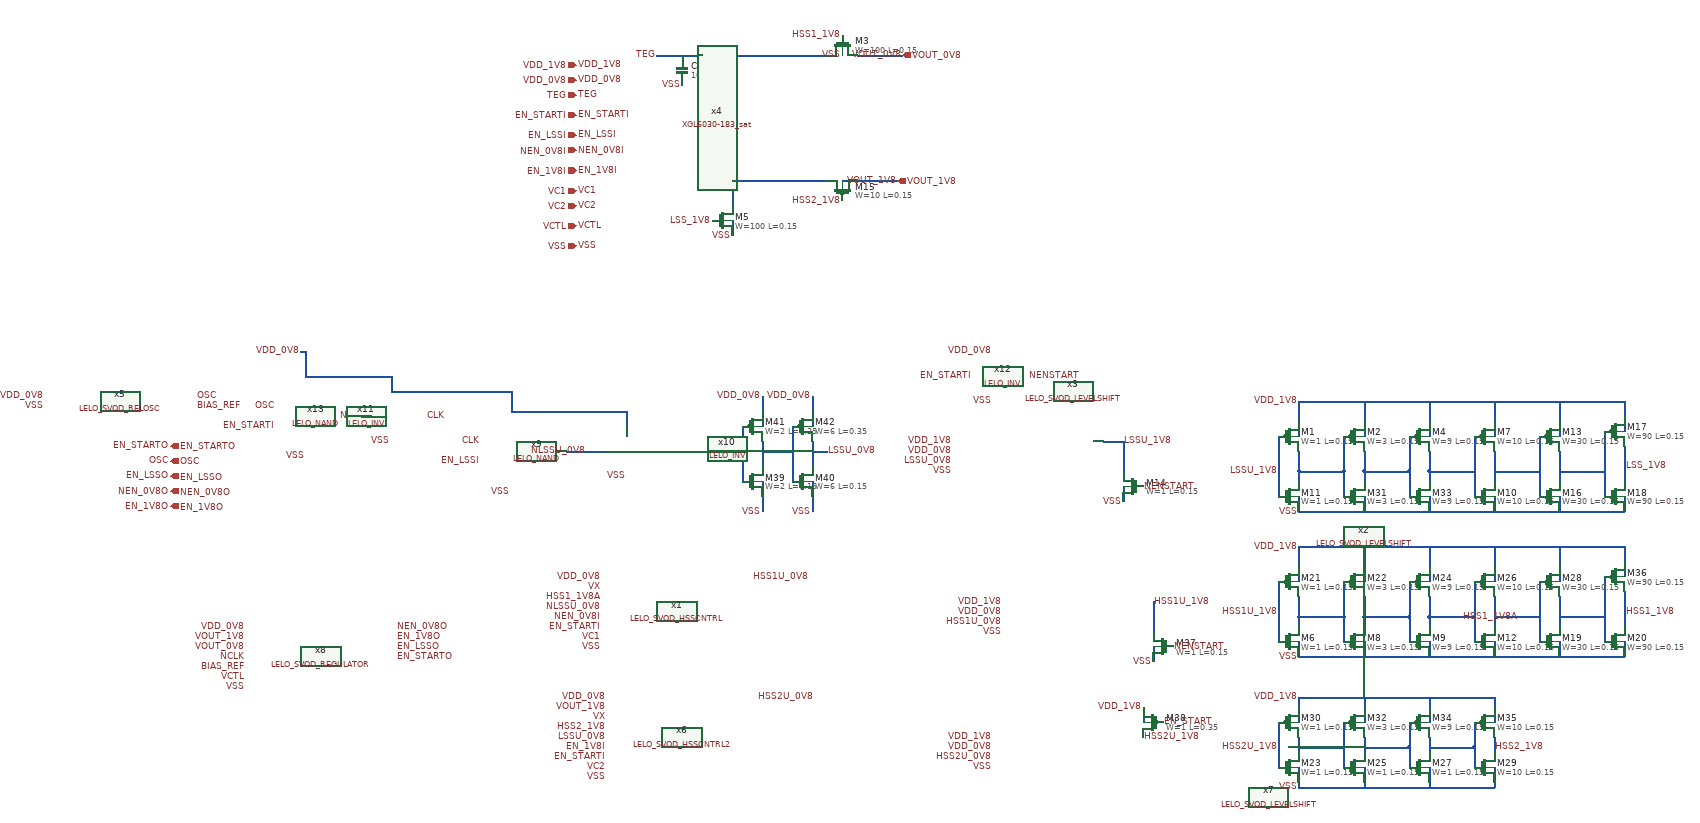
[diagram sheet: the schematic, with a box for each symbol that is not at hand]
v {xschem version=3.4.6 file_version=1.2}
G {}
K {}
V {}
S {}
E {}
N -350 -940 -290 -940 {lab=VX}
N -480 -940 -350 -940 {lab=VX}
N -480 -940 -480 -780 {lab=VX}
N -560 -940 -540 -940 {lab=TEG}
N 650 -60 650 -30 {lab=VSS}
N 1040 -150 1040 -90 {lab=#net1}
N 1040 -60 1040 -30 {lab=VSS}
N 1000 -180 1000 -60 {lab=#net2}
N 650 -110 740 -110 {lab=#net3}
N -580 -940 -560 -940 {lab=TEG}
N 1170 -150 1170 -90 {lab=#net4}
N 1170 -60 1170 -30 {lab=VSS}
N 1130 -180 1130 -60 {lab=#net1}
N 1040 -110 1130 -110 {lab=#net1}
N 1300 -160 1300 -90 {lab=LSS_1V8}
N 1300 -60 1300 -30 {lab=VSS}
N 1260 -190 1260 -60 {lab=#net4}
N 1170 -110 1260 -110 {lab=#net4}
N -230 -940 -140 -940 {lab=VOUT_0V8}
N 650 -250 1230 -250 {lab=VDD_1V8}
N 1040 -250 1040 -210 {lab=VDD_1V8}
N 1170 -250 1170 -210 {lab=VDD_1V8}
N 1300 -250 1300 -220 {lab=VDD_1V8}
N 650 -250 650 -210 {lab=VDD_1V8}
N 650 -150 650 -110 {lab=#net3}
N 650 -110 650 -90 {lab=#net3}
N 610 -180 610 -110 {lab=LSSU_1V8}
N 610 -110 610 -60 {lab=LSSU_1V8}
N 650 -210 650 -180 {lab=VDD_1V8}
N 1040 -210 1040 -180 {lab=VDD_1V8}
N 1170 -210 1170 -180 {lab=VDD_1V8}
N 1300 -220 1300 -190 {lab=VDD_1V8}
N 780 -60 780 -30 {lab=VSS}
N 780 -110 870 -110 {lab=#net5}
N 780 -250 780 -210 {lab=VDD_1V8}
N 780 -150 780 -110 {lab=#net5}
N 780 -110 780 -90 {lab=#net5}
N 740 -180 740 -110 {lab=#net3}
N 740 -110 740 -60 {lab=#net3}
N 780 -210 780 -180 {lab=VDD_1V8}
N 910 -60 910 -30 {lab=VSS}
N 910 -110 1000 -110 {lab=#net2}
N 910 -250 910 -210 {lab=VDD_1V8}
N 910 -150 910 -110 {lab=#net2}
N 910 -110 910 -90 {lab=#net2}
N 870 -180 870 -110 {lab=#net5}
N 870 -110 870 -60 {lab=#net5}
N 910 -210 910 -180 {lab=VDD_1V8}
N -480 -780 -480 -700 {lab=VX}
N -480 -700 -480 -640 {lab=VX}
N -480 -610 -480 -580 {lab=VSS}
N 1230 -250 1300 -250 {lab=VDD_1V8}
N 650 -30 1300 -30 {lab=VSS}
N -480 -690 -290 -690 {lab=VX}
N -260 -690 -230 -690 {lab=VOUT_1V8}
N -230 -690 -150 -690 {lab=VOUT_1V8}
N 650 340 650 360 {lab=VDD_1V8}
N 780 340 780 360 {lab=VDD_1V8}
N 650 480 650 510 {lab=VSS}
N 780 480 780 510 {lab=VSS}
N 610 390 610 440 {lab=HSS2U_1V8}
N 610 440 610 480 {lab=HSS2U_1V8}
N 650 420 650 450 {lab=#net6}
N 650 510 650 520 {lab=VSS}
N 650 440 740 440 {lab=#net6}
N 740 390 740 440 {lab=#net6}
N 740 440 740 480 {lab=#net6}
N 780 420 780 450 {lab=#net7}
N 780 510 780 520 {lab=VSS}
N 910 340 910 360 {lab=VDD_1V8}
N 910 480 910 510 {lab=VSS}
N 780 440 870 440 {lab=#net7}
N 870 390 870 440 {lab=#net7}
N 870 440 870 480 {lab=#net7}
N 910 420 910 450 {lab=#net8}
N 910 510 910 520 {lab=VSS}
N 1040 340 1040 360 {lab=VDD_1V8}
N 1040 480 1040 510 {lab=VSS}
N 1000 390 1000 440 {lab=#net8}
N 1000 440 1000 480 {lab=#net8}
N 1040 420 1040 450 {lab=HSS2_1V8}
N 1040 510 1040 520 {lab=VSS}
N 650 360 650 390 {lab=VDD_1V8}
N 780 360 780 390 {lab=VDD_1V8}
N 910 360 910 390 {lab=VDD_1V8}
N 910 440 1000 440 {lab=#net8}
N 650 340 1040 340 {lab=VDD_1V8}
N 1040 360 1040 390 {lab=VDD_1V8}
N 650 520 1040 520 {lab=VSS}
N -810 -150 -730 -150 {lab=NLSSU_0V8}
N -1220 -220 -1200 -220 {lab=NCLK}
N -630 -940 -580 -940 {lab=TEG}
N 260 -170 300 -170 {lab=LSSU_1V8}
N 300 -80 300 -50 {lab=VSS}
N 300 -170 300 -110 {lab=LSSU_1V8}
N 360 240 360 270 {lab=VSS}
N 360 150 360 210 {lab=HSS1U_1V8}
N 340 360 340 390 {lab=VDD_1V8}
N -1340 -350 -1330 -350 {lab=VDD_0V8}
N -1330 -350 -1330 -300 {lab=VDD_0V8}
N -1330 -300 -1160 -300 {lab=VDD_0V8}
N -1160 -300 -1160 -270 {lab=VDD_0V8}
N -1160 -270 -920 -270 {lab=VDD_0V8}
N -920 -270 -920 -230 {lab=VDD_0V8}
N -920 -230 -690 -230 {lab=VDD_0V8}
N -690 -230 -690 -200 {lab=VDD_0V8}
N 650 230 650 260 {lab=VSS}
N 1040 140 1040 200 {lab=HSS1_1V8A}
N 1040 230 1040 260 {lab=VSS}
N 1000 110 1000 230 {lab=#net9}
N 650 180 740 180 {lab=#net10}
N 1170 140 1170 200 {lab=#net11}
N 1170 230 1170 260 {lab=VSS}
N 1130 110 1130 230 {lab=HSS1_1V8A}
N 1040 180 1130 180 {lab=HSS1_1V8A}
N 1300 130 1300 200 {lab=HSS1_1V8}
N 1300 230 1300 260 {lab=VSS}
N 1260 100 1260 230 {lab=#net11}
N 1170 180 1260 180 {lab=#net11}
N 650 40 1230 40 {lab=VDD_1V8}
N 1040 40 1040 80 {lab=VDD_1V8}
N 1170 40 1170 80 {lab=VDD_1V8}
N 1300 40 1300 70 {lab=VDD_1V8}
N 650 40 650 80 {lab=VDD_1V8}
N 650 140 650 180 {lab=#net10}
N 650 180 650 200 {lab=#net10}
N 610 110 610 180 {lab=HSS1U_1V8}
N 610 180 610 230 {lab=HSS1U_1V8}
N 650 80 650 110 {lab=VDD_1V8}
N 1040 80 1040 110 {lab=VDD_1V8}
N 1170 80 1170 110 {lab=VDD_1V8}
N 1300 70 1300 100 {lab=VDD_1V8}
N 780 230 780 260 {lab=VSS}
N 780 180 870 180 {lab=#net12}
N 780 40 780 80 {lab=VDD_1V8}
N 780 140 780 180 {lab=#net12}
N 780 180 780 200 {lab=#net12}
N 740 110 740 180 {lab=#net10}
N 740 180 740 230 {lab=#net10}
N 780 80 780 110 {lab=VDD_1V8}
N 910 230 910 260 {lab=VSS}
N 910 180 1000 180 {lab=#net9}
N 910 40 910 80 {lab=VDD_1V8}
N 910 140 910 180 {lab=#net9}
N 910 180 910 200 {lab=#net9}
N 870 110 870 180 {lab=#net12}
N 870 180 870 230 {lab=#net12}
N 910 80 910 110 {lab=VDD_1V8}
N 1230 40 1300 40 {lab=VDD_1V8}
N 650 260 1300 260 {lab=VSS}
N -490 -150 -460 -150 {lab=#net13}
N -420 -170 -420 -120 {lab=#net14}
N -420 -90 -420 -60 {lab=VSS}
N -420 -230 -420 -200 {lab=VDD}
N -460 -200 -460 -90 {lab=#net13}
N -420 -60 -420 -30 {lab=VSS}
N -420 -260 -420 -230 {lab=VDD}
N -420 -150 -390 -150 {lab=#net14}
N -390 -150 -360 -150 {lab=#net14}
N -320 -170 -320 -120 {lab=LSSU_0V8}
N -320 -90 -320 -60 {lab=VSS}
N -320 -230 -320 -200 {lab=VDD}
N -360 -200 -360 -90 {lab=#net14}
N -320 -60 -320 -30 {lab=VSS}
N -320 -260 -320 -230 {lab=VDD}
N -320 -150 -290 -150 {lab=LSSU_0V8}
N -620 -150 -490 -150 {lab=#net13}
C {devices/lab_pin.sym} -480 -940 3 1 {name=p3 sig_type=std_logic lab=VX}
C {devices/lab_pin.sym} 1300 -120 0 1 {name=p30 sig_type=std_logic lab=LSS_1V8}
C {devices/capa.sym} -580 -910 0 1 {name=C1
m=1
value=100u
footprint=1206
device="ceramic capacitor"}
C {sky130_fd_pr/nfet_01v8_lvt.sym} -500 -610 0 0 {name=M5
W=100
L=0.15
nf=1
mult=144
ad="expr('int((@nf + 1)/2) * @W / @nf * 0.29')"
pd="expr('2*int((@nf + 1)/2) * (@W / @nf + 0.29)')"
as="expr('int((@nf + 2)/2) * @W / @nf * 0.29')"
ps="expr('2*int((@nf + 2)/2) * (@W / @nf + 0.29)')"
nrd="expr('0.29 / @W ')" nrs="expr('0.29 / @W ')"
sa=0 sb=0 sd=0
model=nfet_01v8_lvt
spiceprefix=X
}
C {devices/lab_pin.sym} -630 -940 2 1 {name=p93 sig_type=std_logic lab=TEG}
C {devices/lab_pin.sym} -140 -940 1 0 {name=p35 sig_type=std_logic lab=VOUT_0V8}
C {sky130_fd_pr/nfet_01v8.sym} 630 -60 0 0 {name=M11
W=1
L=0.15
nf=1 
mult=1
ad="expr('int((@nf + 1)/2) * @W / @nf * 0.29')"
pd="expr('2*int((@nf + 1)/2) * (@W / @nf + 0.29)')"
as="expr('int((@nf + 2)/2) * @W / @nf * 0.29')"
ps="expr('2*int((@nf + 2)/2) * (@W / @nf + 0.29)')"
nrd="expr('0.29 / @W ')" nrs="expr('0.29 / @W ')"
sa=0 sb=0 sd=0
model=nfet_01v8
spiceprefix=X
}
C {sky130_fd_pr/nfet_01v8.sym} 760 -60 0 0 {name=M31
W=3
L=0.15
nf=1 
mult=1
ad="expr('int((@nf + 1)/2) * @W / @nf * 0.29')"
pd="expr('2*int((@nf + 1)/2) * (@W / @nf + 0.29)')"
as="expr('int((@nf + 2)/2) * @W / @nf * 0.29')"
ps="expr('2*int((@nf + 2)/2) * (@W / @nf + 0.29)')"
nrd="expr('0.29 / @W ')" nrs="expr('0.29 / @W ')"
sa=0 sb=0 sd=0
model=nfet_01v8
spiceprefix=X
}
C {sky130_fd_pr/nfet_01v8.sym} 890 -60 0 0 {name=M33
W=9
L=0.15
nf=1 
mult=1
ad="expr('int((@nf + 1)/2) * @W / @nf * 0.29')"
pd="expr('2*int((@nf + 1)/2) * (@W / @nf + 0.29)')"
as="expr('int((@nf + 2)/2) * @W / @nf * 0.29')"
ps="expr('2*int((@nf + 2)/2) * (@W / @nf + 0.29)')"
nrd="expr('0.29 / @W ')" nrs="expr('0.29 / @W ')"
sa=0 sb=0 sd=0
model=nfet_01v8
spiceprefix=X
}
C {devices/lab_pin.sym} -260 -980 1 0 {name=p101 sig_type=std_logic lab=HSS1_1V8}
C {sky130_fd_pr/nfet_01v8_lvt.sym} -260 -960 3 1 {name=M3
W=100
L=0.15
nf=1
mult=38
ad="expr('int((@nf + 1)/2) * @W / @nf * 0.29')"
pd="expr('2*int((@nf + 1)/2) * (@W / @nf + 0.29)')"
as="expr('int((@nf + 2)/2) * @W / @nf * 0.29')"
ps="expr('2*int((@nf + 2)/2) * (@W / @nf + 0.29)')"
nrd="expr('0.29 / @W ')" nrs="expr('0.29 / @W ')"
sa=0 sb=0 sd=0
model=nfet_01v8_lvt
spiceprefix=X
}
C {devices/lab_pin.sym} -290 -150 0 1 {name=p10 sig_type=std_logic lab=LSSU_0V8}
C {LELO_SVOD_SKY130A/LELO_SVOD_HSSCNTRL.sym} -590 170 0 0 {name=x1}
C {devices/lab_pin.sym} -440 100 2 0 {name=p22 sig_type=std_logic lab=HSS1U_0V8}
C {devices/lab_pin.sym} -740 120 2 1 {name=p26 sig_type=std_logic lab=VX}
C {LELO_SVOD_SKY130A/LELO_SVOD_LEVELSHIFT.sym} 210 180 0 0 {name=x2}
C {LELO_SVOD_SKY130A/LELO_SVOD_LEVELSHIFT.sym} 110 -140 0 0 {name=x3}
C {devices/lab_pin.sym} 300 -170 0 1 {name=p23 sig_type=std_logic lab=LSSU_1V8}
C {devices/lab_pin.sym} -1850 -260 0 0 {name=p17 sig_type=std_logic lab=VDD_0V8}
C {devices/lab_pin.sym} -740 100 0 0 {name=p21 sig_type=std_logic lab=VDD_0V8}
C {devices/lab_pin.sym} 60 170 0 0 {name=p28 sig_type=std_logic lab=VDD_0V8}
C {devices/lab_pin.sym} -40 -150 0 0 {name=p29 sig_type=std_logic lab=VDD_0V8}
C {devices/lab_pin.sym} 60 150 0 0 {name=p31 sig_type=std_logic lab=VDD_1V8}
C {devices/lab_pin.sym} -40 -170 0 0 {name=p32 sig_type=std_logic lab=VDD_1V8}
C {devices/lab_pin.sym} -520 -610 0 0 {name=p36 sig_type=std_logic lab=LSS_1V8}
C {devices/lab_pin.sym} -40 -130 0 0 {name=p37 sig_type=std_logic lab=LSSU_0V8}
C {devices/lab_pin.sym} 610 -110 0 0 {name=p38 sig_type=std_logic lab=LSSU_1V8}
C {devices/lab_pin.sym} 1300 170 2 0 {name=p39 sig_type=std_logic lab=HSS1_1V8}
C {devices/ipin.sym} -790 -560 0 0 {name=p40 lab=VSS}
C {devices/lab_pin.sym} -790 -560 2 0 {name=p41 sig_type=std_logic lab=VSS}
C {LELO_SVOD_SKY130A/XGL6030-183_sat.sym} -510 -940 1 0 {name=x4}
C {LELO_SVOD_SKY130A/LELO_SVOD_RELOSC.sym} -1700 -250 0 0 {name=x5}
C {sky130_fd_pr/pfet_01v8.sym} -260 -670 1 1 {name=M15
W=10
L=0.15
nf=1
mult=28
ad="expr('int((@nf + 1)/2) * @W / @nf * 0.29')"
pd="expr('2*int((@nf + 1)/2) * (@W / @nf + 0.29)')"
as="expr('int((@nf + 2)/2) * @W / @nf * 0.29')"
ps="expr('2*int((@nf + 2)/2) * (@W / @nf + 0.29)')"
nrd="expr('0.29 / @W ')" nrs="expr('0.29 / @W ')"
sa=0 sb=0 sd=0
model=pfet_01v8
spiceprefix=X
}
C {devices/lab_pin.sym} -150 -690 1 0 {name=p45 sig_type=std_logic lab=VOUT_1V8}
C {LELO_SVOD_SKY130A/LELO_SVOD_HSSCNTRL2.sym} -580 420 0 0 {name=x6}
C {devices/lab_pin.sym} -730 380 2 1 {name=p48 sig_type=std_logic lab=VX}
C {devices/lab_pin.sym} -730 340 0 0 {name=p50 sig_type=std_logic lab=VDD_0V8}
C {devices/lab_pin.sym} -730 360 0 0 {name=p53 sig_type=std_logic lab=VOUT_1V8}
C {devices/lab_pin.sym} -730 420 0 0 {name=p54 sig_type=std_logic lab=LSSU_0V8}
C {devices/lab_pin.sym} -430 340 2 0 {name=p57 sig_type=std_logic lab=HSS2U_0V8}
C {LELO_SVOD_SKY130A/LELO_SVOD_LEVELSHIFT.sym} 190 450 0 0 {name=x7}
C {devices/lab_pin.sym} 340 420 2 0 {name=p58 sig_type=std_logic lab=HSS2U_1V8}
C {devices/lab_pin.sym} 40 440 0 0 {name=p61 sig_type=std_logic lab=VDD_0V8}
C {devices/lab_pin.sym} 40 420 0 0 {name=p62 sig_type=std_logic lab=VDD_1V8}
C {devices/lab_pin.sym} 40 460 2 1 {name=p60 sig_type=std_logic lab=HSS2U_0V8}
C {sky130_fd_pr/nfet_01v8.sym} 630 480 0 0 {name=M23
W=1
L=0.15
nf=1 
mult=1
ad="expr('int((@nf + 1)/2) * @W / @nf * 0.29')"
pd="expr('2*int((@nf + 1)/2) * (@W / @nf + 0.29)')"
as="expr('int((@nf + 2)/2) * @W / @nf * 0.29')"
ps="expr('2*int((@nf + 2)/2) * (@W / @nf + 0.29)')"
nrd="expr('0.29 / @W ')" nrs="expr('0.29 / @W ')"
sa=0 sb=0 sd=0
model=nfet_01v8
spiceprefix=X
}
C {sky130_fd_pr/nfet_01v8.sym} 760 480 0 0 {name=M25
W=1
L=0.15
nf=1 
mult=3
ad="expr('int((@nf + 1)/2) * @W / @nf * 0.29')"
pd="expr('2*int((@nf + 1)/2) * (@W / @nf + 0.29)')"
as="expr('int((@nf + 2)/2) * @W / @nf * 0.29')"
ps="expr('2*int((@nf + 2)/2) * (@W / @nf + 0.29)')"
nrd="expr('0.29 / @W ')" nrs="expr('0.29 / @W ')"
sa=0 sb=0 sd=0
model=nfet_01v8
spiceprefix=X
}
C {sky130_fd_pr/nfet_01v8.sym} 890 480 0 0 {name=M27
W=1
L=0.15
nf=1 
mult=9
ad="expr('int((@nf + 1)/2) * @W / @nf * 0.29')"
pd="expr('2*int((@nf + 1)/2) * (@W / @nf + 0.29)')"
as="expr('int((@nf + 2)/2) * @W / @nf * 0.29')"
ps="expr('2*int((@nf + 2)/2) * (@W / @nf + 0.29)')"
nrd="expr('0.29 / @W ')" nrs="expr('0.29 / @W ')"
sa=0 sb=0 sd=0
model=nfet_01v8
spiceprefix=X
}
C {sky130_fd_pr/nfet_01v8.sym} 1020 480 0 0 {name=M29
W=10
L=0.15
nf=1 
mult=3
ad="expr('int((@nf + 1)/2) * @W / @nf * 0.29')"
pd="expr('2*int((@nf + 1)/2) * (@W / @nf + 0.29)')"
as="expr('int((@nf + 2)/2) * @W / @nf * 0.29')"
ps="expr('2*int((@nf + 2)/2) * (@W / @nf + 0.29)')"
nrd="expr('0.29 / @W ')" nrs="expr('0.29 / @W ')"
sa=0 sb=0 sd=0
model=nfet_01v8
spiceprefix=X
}
C {devices/lab_pin.sym} 650 340 0 0 {name=p65 sig_type=std_logic lab=VDD_1V8}
C {devices/lab_pin.sym} 1040 440 2 0 {name=p66 sig_type=std_logic lab=HSS2_1V8}
C {devices/lab_pin.sym} 610 440 2 1 {name=p64 sig_type=std_logic lab=HSS2U_1V8}
C {devices/lab_pin.sym} -730 400 2 1 {name=p67 sig_type=std_logic lab=HSS2_1V8}
C {devices/lab_pin.sym} -260 -650 1 1 {name=p68 sig_type=std_logic lab=HSS2_1V8}
C {LELO_SVOD_SKY130A/LELO_SVOD_REGULATOR.sym} -1300 260 0 0 {name=x8}
C {devices/lab_pin.sym} -1450 240 0 0 {name=p71 sig_type=std_logic lab=VOUT_0V8}
C {devices/lab_pin.sym} -1450 220 0 0 {name=p72 sig_type=std_logic lab=VOUT_1V8}
C {devices/lab_pin.sym} -1450 200 0 0 {name=p46 sig_type=std_logic lab=VDD_0V8}
C {devices/lab_pin.sym} -1210 -220 3 1 {name=p76 sig_type=std_logic lab=NCLK}
C {LELO_SVOD_SKY130A/LELO_NAND.sym} -900 -150 0 0 {name=x9}
C {LELO_SVOD_SKY130A/LELO_INV.sym} -670 -150 0 0 {name=x10}
C {devices/lab_pin.sym} -1450 260 0 0 {name=p74 sig_type=std_logic lab=NCLK}
C {devices/lab_pin.sym} -1090 -220 0 1 {name=p84 sig_type=std_logic lab=CLK}
C {devices/lab_pin.sym} -980 -170 0 0 {name=p78 sig_type=std_logic lab=CLK}
C {devices/lab_pin.sym} -770 -150 1 1 {name=p86 sig_type=std_logic lab=NLSSU_0V8}
C {devices/lab_pin.sym} -480 -580 3 0 {name=p1 sig_type=std_logic lab=VSS}
C {devices/lab_pin.sym} -920 -70 3 0 {name=p12 sig_type=std_logic lab=VSS}
C {devices/lab_pin.sym} -1160 -170 3 0 {name=p13 sig_type=std_logic lab=VSS}
C {LELO_SVOD_SKY130A/LELO_INV.sym} -1140 -220 0 0 {name=x11}
C {devices/lab_pin.sym} -1450 320 0 0 {name=p14 sig_type=std_logic lab=VSS}
C {devices/lab_pin.sym} -740 240 0 0 {name=p15 sig_type=std_logic lab=VSS}
C {devices/lab_pin.sym} -730 500 0 0 {name=p16 sig_type=std_logic lab=VSS}
C {devices/lab_pin.sym} 40 480 0 0 {name=p19 sig_type=std_logic lab=VSS}
C {devices/lab_pin.sym} 60 210 0 0 {name=p20 sig_type=std_logic lab=VSS}
C {devices/lab_pin.sym} -40 -110 0 0 {name=p24 sig_type=std_logic lab=VSS}
C {devices/lab_pin.sym} 650 520 0 0 {name=p43 sig_type=std_logic lab=VSS}
C {devices/lab_pin.sym} 650 -30 0 0 {name=p44 sig_type=std_logic lab=VSS}
C {devices/lab_pin.sym} -1850 -240 0 0 {name=p47 sig_type=std_logic lab=VSS}
C {devices/lab_pin.sym} -580 -880 3 0 {name=p7 sig_type=std_logic lab=VSS}
C {devices/lab_pin.sym} -260 -940 3 0 {name=p6 sig_type=std_logic lab=VSS}
C {devices/lab_pin.sym} -690 -100 3 0 {name=p52 sig_type=std_logic lab=VSS}
C {devices/ipin.sym} -790 -860 0 0 {name=p56 lab=TEG}
C {devices/lab_pin.sym} -790 -860 2 0 {name=p59 sig_type=std_logic lab=TEG}
C {devices/lab_pin.sym} -790 -890 0 1 {name=p63 sig_type=std_logic lab=VDD_0V8}
C {devices/ipin.sym} -790 -890 0 0 {name=p73 lab=VDD_0V8}
C {devices/lab_pin.sym} -790 -920 0 1 {name=p75 sig_type=std_logic lab=VDD_1V8}
C {devices/ipin.sym} -790 -920 0 0 {name=p77 lab=VDD_1V8}
C {devices/opin.sym} -140 -940 0 0 {name=p2 lab=VOUT_0V8}
C {devices/opin.sym} -150 -690 0 0 {name=p79 lab=VOUT_1V8}
C {LELO_SVOD_SKY130A/LELO_NAND.sym} -1310 -220 0 0 {name=x13}
C {devices/lab_pin.sym} -1340 -350 0 0 {name=p80 sig_type=std_logic lab=VDD_0V8}
C {devices/lab_pin.sym} -1330 -140 3 0 {name=p89 sig_type=std_logic lab=VSS}
C {devices/lab_pin.sym} -1550 -260 0 1 {name=p90 sig_type=std_logic lab=OSC}
C {devices/opin.sym} -1600 -160 0 0 {name=p94 lab=EN_STARTO}
C {devices/lab_pin.sym} -1600 -160 0 0 {name=p95 sig_type=std_logic lab=EN_STARTO}
C {devices/opin.sym} -1600 -130 0 0 {name=p96 lab=OSC}
C {devices/lab_pin.sym} -1600 -130 0 0 {name=p97 sig_type=std_logic lab=OSC}
C {devices/lab_pin.sym} 300 -50 0 0 {name=p98 sig_type=std_logic lab=VSS}
C {sky130_fd_pr/nfet_01v8_lvt.sym} 320 -80 0 1 {name=M14
W=1
L=0.15
nf=1
mult=1
ad="expr('int((@nf + 1)/2) * @W / @nf * 0.29')"
pd="expr('2*int((@nf + 1)/2) * (@W / @nf + 0.29)')"
as="expr('int((@nf + 2)/2) * @W / @nf * 0.29')"
ps="expr('2*int((@nf + 2)/2) * (@W / @nf + 0.29)')"
nrd="expr('0.29 / @W ')" nrs="expr('0.29 / @W ')"
sa=0 sb=0 sd=0
model=nfet_01v8_lvt
spiceprefix=X
}
C {devices/lab_pin.sym} -1550 -240 0 1 {name=p109 sig_type=std_logic lab=BIAS_REF}
C {devices/lab_pin.sym} -1390 -240 0 0 {name=p110 sig_type=std_logic lab=OSC}
C {devices/lab_pin.sym} 610 170 0 0 {name=p33 sig_type=std_logic lab=HSS1U_1V8}
C {devices/lab_pin.sym} 1090 180 1 0 {name=p42 sig_type=std_logic lab=HSS1_1V8A}
C {devices/lab_pin.sym} -740 140 0 0 {name=p106 sig_type=std_logic lab=HSS1_1V8A}
C {devices/lab_pin.sym} -1450 280 0 0 {name=p27 sig_type=std_logic lab=BIAS_REF}
C {devices/lab_pin.sym} -740 160 2 1 {name=p25 sig_type=std_logic lab=NLSSU_0V8}
C {devices/lab_pin.sym} 60 190 2 1 {name=p5 sig_type=std_logic lab=HSS1U_0V8}
C {devices/lab_pin.sym} 360 150 0 1 {name=p8 sig_type=std_logic lab=HSS1U_1V8}
C {sky130_fd_pr/nfet_01v8.sym} 1020 -60 0 0 {name=M10
W=10
L=0.15
nf=1 
mult=3
ad="expr('int((@nf + 1)/2) * @W / @nf * 0.29')"
pd="expr('2*int((@nf + 1)/2) * (@W / @nf + 0.29)')"
as="expr('int((@nf + 2)/2) * @W / @nf * 0.29')"
ps="expr('2*int((@nf + 2)/2) * (@W / @nf + 0.29)')"
nrd="expr('0.29 / @W ')" nrs="expr('0.29 / @W ')"
sa=0 sb=0 sd=0
model=nfet_01v8
spiceprefix=X
}
C {sky130_fd_pr/nfet_01v8.sym} 1150 -60 0 0 {name=M16
W=30
L=0.15
nf=1 
mult=3
ad="expr('int((@nf + 1)/2) * @W / @nf * 0.29')"
pd="expr('2*int((@nf + 1)/2) * (@W / @nf + 0.29)')"
as="expr('int((@nf + 2)/2) * @W / @nf * 0.29')"
ps="expr('2*int((@nf + 2)/2) * (@W / @nf + 0.29)')"
nrd="expr('0.29 / @W ')" nrs="expr('0.29 / @W ')"
sa=0 sb=0 sd=0
model=nfet_01v8
spiceprefix=X
}
C {sky130_fd_pr/nfet_01v8.sym} 1280 -60 0 0 {name=M18
W=90
L=0.15
nf=1 
mult=3
ad="expr('int((@nf + 1)/2) * @W / @nf * 0.29')"
pd="expr('2*int((@nf + 1)/2) * (@W / @nf + 0.29)')"
as="expr('int((@nf + 2)/2) * @W / @nf * 0.29')"
ps="expr('2*int((@nf + 2)/2) * (@W / @nf + 0.29)')"
nrd="expr('0.29 / @W ')" nrs="expr('0.29 / @W ')"
sa=0 sb=0 sd=0
model=nfet_01v8
spiceprefix=X
}
C {devices/lab_pin.sym} 360 270 0 0 {name=p4 sig_type=std_logic lab=VSS}
C {sky130_fd_pr/nfet_01v8_lvt.sym} 380 240 0 1 {name=M37
W=1
L=0.15
nf=1
mult=1
ad="expr('int((@nf + 1)/2) * @W / @nf * 0.29')"
pd="expr('2*int((@nf + 1)/2) * (@W / @nf + 0.29)')"
as="expr('int((@nf + 2)/2) * @W / @nf * 0.29')"
ps="expr('2*int((@nf + 2)/2) * (@W / @nf + 0.29)')"
nrd="expr('0.29 / @W ')" nrs="expr('0.29 / @W ')"
sa=0 sb=0 sd=0
model=nfet_01v8_lvt
spiceprefix=X
}
C {sky130_fd_pr/pfet_01v8_lvt.sym} 360 390 0 1 {name=M38
W=1
L=0.35
nf=1
mult=1
ad="expr('int((@nf + 1)/2) * @W / @nf * 0.29')"
pd="expr('2*int((@nf + 1)/2) * (@W / @nf + 0.29)')"
as="expr('int((@nf + 2)/2) * @W / @nf * 0.29')"
ps="expr('2*int((@nf + 2)/2) * (@W / @nf + 0.29)')"
nrd="expr('0.29 / @W ')" nrs="expr('0.29 / @W ')"
sa=0 sb=0 sd=0
model=pfet_01v8_lvt
spiceprefix=X
}
C {devices/lab_pin.sym} 340 360 0 0 {name=p49 sig_type=std_logic lab=VDD_1V8}
C {devices/lab_pin.sym} 380 390 0 1 {name=p91 sig_type=std_logic lab=EN_START}
C {devices/lab_pin.sym} 650 -250 0 0 {name=p51 sig_type=std_logic lab=VDD_1V8}
C {LELO_SVOD_SKY130A/LELO_INV.sym} 60 -300 0 0 {name=x12}
C {devices/lab_pin.sym} 40 -250 3 0 {name=p34 sig_type=std_logic lab=VSS}
C {devices/lab_pin.sym} 40 -350 0 0 {name=p81 sig_type=std_logic lab=VDD_0V8}
C {devices/lab_pin.sym} 110 -300 0 1 {name=p82 sig_type=std_logic lab=NENSTART}
C {devices/lab_pin.sym} 340 -80 0 1 {name=p87 sig_type=std_logic lab=NENSTART}
C {devices/lab_pin.sym} 400 240 0 1 {name=p88 sig_type=std_logic lab=NENSTART}
C {devices/opin.sym} -1600 -100 0 0 {name=p103 lab=EN_LSSO}
C {devices/lab_pin.sym} -1600 -100 0 0 {name=p107 sig_type=std_logic lab=EN_LSSO}
C {devices/opin.sym} -1600 -70 0 0 {name=p108 lab=NEN_0V8O}
C {devices/lab_pin.sym} -1600 -70 0 0 {name=p111 sig_type=std_logic lab=NEN_0V8O}
C {devices/opin.sym} -1600 -40 0 0 {name=p112 lab=EN_1V8O}
C {devices/lab_pin.sym} -1600 -40 0 0 {name=p113 sig_type=std_logic lab=EN_1V8O}
C {devices/lab_pin.sym} -1150 200 0 1 {name=p11 sig_type=std_logic lab=NEN_0V8O}
C {devices/lab_pin.sym} -1150 220 0 1 {name=p18 sig_type=std_logic lab=EN_1V8O}
C {devices/lab_pin.sym} -1150 240 0 1 {name=p69 sig_type=std_logic lab=EN_LSSO}
C {devices/lab_pin.sym} -1150 260 0 1 {name=p85 sig_type=std_logic lab=EN_STARTO}
C {devices/ipin.sym} -790 -820 0 0 {name=p92 lab=EN_STARTI}
C {devices/lab_pin.sym} -790 -820 2 0 {name=p99 sig_type=std_logic lab=EN_STARTI}
C {devices/lab_pin.sym} -1390 -200 2 1 {name=p100 sig_type=std_logic lab=EN_STARTI}
C {devices/lab_pin.sym} 0 -300 2 1 {name=p9 sig_type=std_logic lab=EN_STARTI}
C {devices/lab_pin.sym} -740 200 2 1 {name=p102 sig_type=std_logic lab=EN_STARTI}
C {devices/lab_pin.sym} -730 460 2 1 {name=p114 sig_type=std_logic lab=EN_STARTI}
C {devices/ipin.sym} -790 -780 0 0 {name=p115 lab=EN_LSSI}
C {devices/lab_pin.sym} -790 -780 2 0 {name=p116 sig_type=std_logic lab=EN_LSSI}
C {devices/lab_pin.sym} -980 -130 2 1 {name=p83 sig_type=std_logic lab=EN_LSSI}
C {devices/ipin.sym} -790 -750 0 0 {name=p117 lab=NEN_0V8I}
C {devices/lab_pin.sym} -790 -750 2 0 {name=p118 sig_type=std_logic lab=NEN_0V8I}
C {devices/lab_pin.sym} -740 180 2 1 {name=p55 sig_type=std_logic lab=NEN_0V8I}
C {devices/ipin.sym} -790 -710 0 0 {name=p70 lab=EN_1V8I}
C {devices/lab_pin.sym} -790 -710 2 0 {name=p119 sig_type=std_logic lab=EN_1V8I}
C {devices/lab_pin.sym} -730 440 2 1 {name=p120 sig_type=std_logic lab=EN_1V8I}
C {sky130_fd_pr/pfet_01v8_hvt.sym} 630 -180 0 0 {name=M1
W=1
L=0.15
nf=1
mult=1
ad="expr('int((@nf + 1)/2) * @W / @nf * 0.29')"
pd="expr('2*int((@nf + 1)/2) * (@W / @nf + 0.29)')"
as="expr('int((@nf + 2)/2) * @W / @nf * 0.29')"
ps="expr('2*int((@nf + 2)/2) * (@W / @nf + 0.29)')"
nrd="expr('0.29 / @W ')" nrs="expr('0.29 / @W ')"
sa=0 sb=0 sd=0
model=pfet_01v8_hvt
spiceprefix=X
}
C {sky130_fd_pr/pfet_01v8_hvt.sym} 760 -180 0 0 {name=M2
W=3
L=0.15
nf=1
mult=1
ad="expr('int((@nf + 1)/2) * @W / @nf * 0.29')"
pd="expr('2*int((@nf + 1)/2) * (@W / @nf + 0.29)')"
as="expr('int((@nf + 2)/2) * @W / @nf * 0.29')"
ps="expr('2*int((@nf + 2)/2) * (@W / @nf + 0.29)')"
nrd="expr('0.29 / @W ')" nrs="expr('0.29 / @W ')"
sa=0 sb=0 sd=0
model=pfet_01v8_hvt
spiceprefix=X
}
C {sky130_fd_pr/pfet_01v8_hvt.sym} 890 -180 0 0 {name=M4
W=9
L=0.15
nf=1
mult=1
ad="expr('int((@nf + 1)/2) * @W / @nf * 0.29')"
pd="expr('2*int((@nf + 1)/2) * (@W / @nf + 0.29)')"
as="expr('int((@nf + 2)/2) * @W / @nf * 0.29')"
ps="expr('2*int((@nf + 2)/2) * (@W / @nf + 0.29)')"
nrd="expr('0.29 / @W ')" nrs="expr('0.29 / @W ')"
sa=0 sb=0 sd=0
model=pfet_01v8_hvt
spiceprefix=X
}
C {sky130_fd_pr/pfet_01v8_hvt.sym} 1020 -180 0 0 {name=M7
W=10
L=0.15
nf=1
mult=3
ad="expr('int((@nf + 1)/2) * @W / @nf * 0.29')"
pd="expr('2*int((@nf + 1)/2) * (@W / @nf + 0.29)')"
as="expr('int((@nf + 2)/2) * @W / @nf * 0.29')"
ps="expr('2*int((@nf + 2)/2) * (@W / @nf + 0.29)')"
nrd="expr('0.29 / @W ')" nrs="expr('0.29 / @W ')"
sa=0 sb=0 sd=0
model=pfet_01v8_hvt
spiceprefix=X
}
C {sky130_fd_pr/pfet_01v8_hvt.sym} 1150 -180 0 0 {name=M13
W=30
L=0.15
nf=1
mult=3
ad="expr('int((@nf + 1)/2) * @W / @nf * 0.29')"
pd="expr('2*int((@nf + 1)/2) * (@W / @nf + 0.29)')"
as="expr('int((@nf + 2)/2) * @W / @nf * 0.29')"
ps="expr('2*int((@nf + 2)/2) * (@W / @nf + 0.29)')"
nrd="expr('0.29 / @W ')" nrs="expr('0.29 / @W ')"
sa=0 sb=0 sd=0
model=pfet_01v8_hvt
spiceprefix=X
}
C {sky130_fd_pr/pfet_01v8_hvt.sym} 1280 -190 0 0 {name=M17
W=90
L=0.15
nf=1
mult=3
ad="expr('int((@nf + 1)/2) * @W / @nf * 0.29')"
pd="expr('2*int((@nf + 1)/2) * (@W / @nf + 0.29)')"
as="expr('int((@nf + 2)/2) * @W / @nf * 0.29')"
ps="expr('2*int((@nf + 2)/2) * (@W / @nf + 0.29)')"
nrd="expr('0.29 / @W ')" nrs="expr('0.29 / @W ')"
sa=0 sb=0 sd=0
model=pfet_01v8_hvt
spiceprefix=X
}
C {sky130_fd_pr/nfet_01v8.sym} 630 230 0 0 {name=M6
W=1
L=0.15
nf=1 
mult=1
ad="expr('int((@nf + 1)/2) * @W / @nf * 0.29')"
pd="expr('2*int((@nf + 1)/2) * (@W / @nf + 0.29)')"
as="expr('int((@nf + 2)/2) * @W / @nf * 0.29')"
ps="expr('2*int((@nf + 2)/2) * (@W / @nf + 0.29)')"
nrd="expr('0.29 / @W ')" nrs="expr('0.29 / @W ')"
sa=0 sb=0 sd=0
model=nfet_01v8
spiceprefix=X
}
C {sky130_fd_pr/nfet_01v8.sym} 760 230 0 0 {name=M8
W=3
L=0.15
nf=1 
mult=1
ad="expr('int((@nf + 1)/2) * @W / @nf * 0.29')"
pd="expr('2*int((@nf + 1)/2) * (@W / @nf + 0.29)')"
as="expr('int((@nf + 2)/2) * @W / @nf * 0.29')"
ps="expr('2*int((@nf + 2)/2) * (@W / @nf + 0.29)')"
nrd="expr('0.29 / @W ')" nrs="expr('0.29 / @W ')"
sa=0 sb=0 sd=0
model=nfet_01v8
spiceprefix=X
}
C {sky130_fd_pr/nfet_01v8.sym} 890 230 0 0 {name=M9
W=9
L=0.15
nf=1 
mult=1
ad="expr('int((@nf + 1)/2) * @W / @nf * 0.29')"
pd="expr('2*int((@nf + 1)/2) * (@W / @nf + 0.29)')"
as="expr('int((@nf + 2)/2) * @W / @nf * 0.29')"
ps="expr('2*int((@nf + 2)/2) * (@W / @nf + 0.29)')"
nrd="expr('0.29 / @W ')" nrs="expr('0.29 / @W ')"
sa=0 sb=0 sd=0
model=nfet_01v8
spiceprefix=X
}
C {devices/lab_pin.sym} 650 260 0 0 {name=p121 sig_type=std_logic lab=VSS}
C {sky130_fd_pr/nfet_01v8.sym} 1020 230 0 0 {name=M12
W=10
L=0.15
nf=1 
mult=3
ad="expr('int((@nf + 1)/2) * @W / @nf * 0.29')"
pd="expr('2*int((@nf + 1)/2) * (@W / @nf + 0.29)')"
as="expr('int((@nf + 2)/2) * @W / @nf * 0.29')"
ps="expr('2*int((@nf + 2)/2) * (@W / @nf + 0.29)')"
nrd="expr('0.29 / @W ')" nrs="expr('0.29 / @W ')"
sa=0 sb=0 sd=0
model=nfet_01v8
spiceprefix=X
}
C {sky130_fd_pr/nfet_01v8.sym} 1150 230 0 0 {name=M19
W=30
L=0.15
nf=1 
mult=3
ad="expr('int((@nf + 1)/2) * @W / @nf * 0.29')"
pd="expr('2*int((@nf + 1)/2) * (@W / @nf + 0.29)')"
as="expr('int((@nf + 2)/2) * @W / @nf * 0.29')"
ps="expr('2*int((@nf + 2)/2) * (@W / @nf + 0.29)')"
nrd="expr('0.29 / @W ')" nrs="expr('0.29 / @W ')"
sa=0 sb=0 sd=0
model=nfet_01v8
spiceprefix=X
}
C {sky130_fd_pr/nfet_01v8.sym} 1280 230 0 0 {name=M20
W=90
L=0.15
nf=1 
mult=3
ad="expr('int((@nf + 1)/2) * @W / @nf * 0.29')"
pd="expr('2*int((@nf + 1)/2) * (@W / @nf + 0.29)')"
as="expr('int((@nf + 2)/2) * @W / @nf * 0.29')"
ps="expr('2*int((@nf + 2)/2) * (@W / @nf + 0.29)')"
nrd="expr('0.29 / @W ')" nrs="expr('0.29 / @W ')"
sa=0 sb=0 sd=0
model=nfet_01v8
spiceprefix=X
}
C {devices/lab_pin.sym} 650 40 0 0 {name=p122 sig_type=std_logic lab=VDD_1V8}
C {sky130_fd_pr/pfet_01v8_hvt.sym} 630 110 0 0 {name=M21
W=1
L=0.15
nf=1
mult=1
ad="expr('int((@nf + 1)/2) * @W / @nf * 0.29')"
pd="expr('2*int((@nf + 1)/2) * (@W / @nf + 0.29)')"
as="expr('int((@nf + 2)/2) * @W / @nf * 0.29')"
ps="expr('2*int((@nf + 2)/2) * (@W / @nf + 0.29)')"
nrd="expr('0.29 / @W ')" nrs="expr('0.29 / @W ')"
sa=0 sb=0 sd=0
model=pfet_01v8_hvt
spiceprefix=X
}
C {sky130_fd_pr/pfet_01v8_hvt.sym} 760 110 0 0 {name=M22
W=3
L=0.15
nf=1
mult=1
ad="expr('int((@nf + 1)/2) * @W / @nf * 0.29')"
pd="expr('2*int((@nf + 1)/2) * (@W / @nf + 0.29)')"
as="expr('int((@nf + 2)/2) * @W / @nf * 0.29')"
ps="expr('2*int((@nf + 2)/2) * (@W / @nf + 0.29)')"
nrd="expr('0.29 / @W ')" nrs="expr('0.29 / @W ')"
sa=0 sb=0 sd=0
model=pfet_01v8_hvt
spiceprefix=X
}
C {sky130_fd_pr/pfet_01v8_hvt.sym} 890 110 0 0 {name=M24
W=9
L=0.15
nf=1
mult=1
ad="expr('int((@nf + 1)/2) * @W / @nf * 0.29')"
pd="expr('2*int((@nf + 1)/2) * (@W / @nf + 0.29)')"
as="expr('int((@nf + 2)/2) * @W / @nf * 0.29')"
ps="expr('2*int((@nf + 2)/2) * (@W / @nf + 0.29)')"
nrd="expr('0.29 / @W ')" nrs="expr('0.29 / @W ')"
sa=0 sb=0 sd=0
model=pfet_01v8_hvt
spiceprefix=X
}
C {sky130_fd_pr/pfet_01v8_hvt.sym} 1020 110 0 0 {name=M26
W=10
L=0.15
nf=1
mult=3
ad="expr('int((@nf + 1)/2) * @W / @nf * 0.29')"
pd="expr('2*int((@nf + 1)/2) * (@W / @nf + 0.29)')"
as="expr('int((@nf + 2)/2) * @W / @nf * 0.29')"
ps="expr('2*int((@nf + 2)/2) * (@W / @nf + 0.29)')"
nrd="expr('0.29 / @W ')" nrs="expr('0.29 / @W ')"
sa=0 sb=0 sd=0
model=pfet_01v8_hvt
spiceprefix=X
}
C {sky130_fd_pr/pfet_01v8_hvt.sym} 1150 110 0 0 {name=M28
W=30
L=0.15
nf=1
mult=3
ad="expr('int((@nf + 1)/2) * @W / @nf * 0.29')"
pd="expr('2*int((@nf + 1)/2) * (@W / @nf + 0.29)')"
as="expr('int((@nf + 2)/2) * @W / @nf * 0.29')"
ps="expr('2*int((@nf + 2)/2) * (@W / @nf + 0.29)')"
nrd="expr('0.29 / @W ')" nrs="expr('0.29 / @W ')"
sa=0 sb=0 sd=0
model=pfet_01v8_hvt
spiceprefix=X
}
C {sky130_fd_pr/pfet_01v8_hvt.sym} 1280 100 0 0 {name=M36
W=90
L=0.15
nf=1
mult=3
ad="expr('int((@nf + 1)/2) * @W / @nf * 0.29')"
pd="expr('2*int((@nf + 1)/2) * (@W / @nf + 0.29)')"
as="expr('int((@nf + 2)/2) * @W / @nf * 0.29')"
ps="expr('2*int((@nf + 2)/2) * (@W / @nf + 0.29)')"
nrd="expr('0.29 / @W ')" nrs="expr('0.29 / @W ')"
sa=0 sb=0 sd=0
model=pfet_01v8_hvt
spiceprefix=X
}
C {sky130_fd_pr/pfet_01v8_hvt.sym} 630 390 0 0 {name=M30
W=1
L=0.15
nf=1
mult=1
ad="expr('int((@nf + 1)/2) * @W / @nf * 0.29')"
pd="expr('2*int((@nf + 1)/2) * (@W / @nf + 0.29)')"
as="expr('int((@nf + 2)/2) * @W / @nf * 0.29')"
ps="expr('2*int((@nf + 2)/2) * (@W / @nf + 0.29)')"
nrd="expr('0.29 / @W ')" nrs="expr('0.29 / @W ')"
sa=0 sb=0 sd=0
model=pfet_01v8_hvt
spiceprefix=X
}
C {sky130_fd_pr/pfet_01v8_hvt.sym} 760 390 0 0 {name=M32
W=3
L=0.15
nf=1
mult=1
ad="expr('int((@nf + 1)/2) * @W / @nf * 0.29')"
pd="expr('2*int((@nf + 1)/2) * (@W / @nf + 0.29)')"
as="expr('int((@nf + 2)/2) * @W / @nf * 0.29')"
ps="expr('2*int((@nf + 2)/2) * (@W / @nf + 0.29)')"
nrd="expr('0.29 / @W ')" nrs="expr('0.29 / @W ')"
sa=0 sb=0 sd=0
model=pfet_01v8_hvt
spiceprefix=X
}
C {sky130_fd_pr/pfet_01v8_hvt.sym} 890 390 0 0 {name=M34
W=9
L=0.15
nf=1
mult=1
ad="expr('int((@nf + 1)/2) * @W / @nf * 0.29')"
pd="expr('2*int((@nf + 1)/2) * (@W / @nf + 0.29)')"
as="expr('int((@nf + 2)/2) * @W / @nf * 0.29')"
ps="expr('2*int((@nf + 2)/2) * (@W / @nf + 0.29)')"
nrd="expr('0.29 / @W ')" nrs="expr('0.29 / @W ')"
sa=0 sb=0 sd=0
model=pfet_01v8_hvt
spiceprefix=X
}
C {sky130_fd_pr/pfet_01v8_hvt.sym} 1020 390 0 0 {name=M35
W=10
L=0.15
nf=1
mult=3
ad="expr('int((@nf + 1)/2) * @W / @nf * 0.29')"
pd="expr('2*int((@nf + 1)/2) * (@W / @nf + 0.29)')"
as="expr('int((@nf + 2)/2) * @W / @nf * 0.29')"
ps="expr('2*int((@nf + 2)/2) * (@W / @nf + 0.29)')"
nrd="expr('0.29 / @W ')" nrs="expr('0.29 / @W ')"
sa=0 sb=0 sd=0
model=pfet_01v8_hvt
spiceprefix=X
}
C {devices/ipin.sym} -790 -670 0 0 {name=p104 lab=VC1}
C {devices/lab_pin.sym} -790 -670 2 0 {name=p105 sig_type=std_logic lab=VC1}
C {devices/ipin.sym} -790 -640 0 0 {name=p123 lab=VC2}
C {devices/lab_pin.sym} -790 -640 2 0 {name=p124 sig_type=std_logic lab=VC2}
C {devices/lab_pin.sym} -740 220 2 1 {name=p125 sig_type=std_logic lab=VC1}
C {devices/lab_pin.sym} -730 480 2 1 {name=p126 sig_type=std_logic lab=VC2}
C {devices/lab_pin.sym} -420 -30 3 0 {name=p128 sig_type=std_logic lab=VSS}
C {sky130_fd_pr/nfet_01v8_lvt.sym} -440 -90 0 0 {name=M39
W=2
L=0.15
nf=1
mult=1
ad="expr('int((@nf + 1)/2) * @W / @nf * 0.29')"
pd="expr('2*int((@nf + 1)/2) * (@W / @nf + 0.29)')"
as="expr('int((@nf + 2)/2) * @W / @nf * 0.29')"
ps="expr('2*int((@nf + 2)/2) * (@W / @nf + 0.29)')"
nrd="expr('0.29 / @W ')" nrs="expr('0.29 / @W ')"
sa=0 sb=0 sd=0
model=nfet_01v8_lvt
spiceprefix=X
}
C {devices/lab_pin.sym} -320 -30 3 0 {name=p129 sig_type=std_logic lab=VSS}
C {sky130_fd_pr/nfet_01v8_lvt.sym} -340 -90 0 0 {name=M40
W=6
L=0.15
nf=1
mult=1
ad="expr('int((@nf + 1)/2) * @W / @nf * 0.29')"
pd="expr('2*int((@nf + 1)/2) * (@W / @nf + 0.29)')"
as="expr('int((@nf + 2)/2) * @W / @nf * 0.29')"
ps="expr('2*int((@nf + 2)/2) * (@W / @nf + 0.29)')"
nrd="expr('0.29 / @W ')" nrs="expr('0.29 / @W ')"
sa=0 sb=0 sd=0
model=nfet_01v8_lvt
spiceprefix=X
}
C {sky130_fd_pr/pfet_01v8_lvt.sym} -440 -200 0 0 {name=M41
W=2
L=0.35
nf=1
mult=1
ad="'int((nf+1)/2) * W/nf * 0.29'" 
pd="'2*int((nf+1)/2) * (W/nf + 0.29)'"
as="'int((nf+2)/2) * W/nf * 0.29'" 
ps="'2*int((nf+2)/2) * (W/nf + 0.29)'"
nrd="'0.29 / W'" nrs="'0.29 / W'"
sa=0 sb=0 sd=0
model=pfet_01v8_lvt
spiceprefix=X
}
C {sky130_fd_pr/pfet_01v8_lvt.sym} -340 -200 0 0 {name=M42
W=6
L=0.35
nf=1
mult=1
ad="'int((nf+1)/2) * W/nf * 0.29'" 
pd="'2*int((nf+1)/2) * (W/nf + 0.29)'"
as="'int((nf+2)/2) * W/nf * 0.29'" 
ps="'2*int((nf+2)/2) * (W/nf + 0.29)'"
nrd="'0.29 / W'" nrs="'0.29 / W'"
sa=0 sb=0 sd=0
model=pfet_01v8_lvt
spiceprefix=X
}
C {devices/lab_pin.sym} -420 -260 0 0 {name=p127 sig_type=std_logic lab=VDD_0V8}
C {devices/lab_pin.sym} -320 -260 0 0 {name=p130 sig_type=std_logic lab=VDD_0V8}
C {devices/ipin.sym} -790 -600 0 0 {name=p131 lab=VCTL}
C {devices/lab_pin.sym} -790 -600 2 0 {name=p132 sig_type=std_logic lab=VCTL}
C {devices/lab_pin.sym} -1450 300 2 1 {name=p133 sig_type=std_logic lab=VCTL}
